VERSION 5.4 ;
NAMESCASESENSITIVE ON ;
BUSBITCHARS "[]" ;
DIVIDERCHAR "/" ;
UNITS
  DATABASE MICRONS 2000 ;
END UNITS
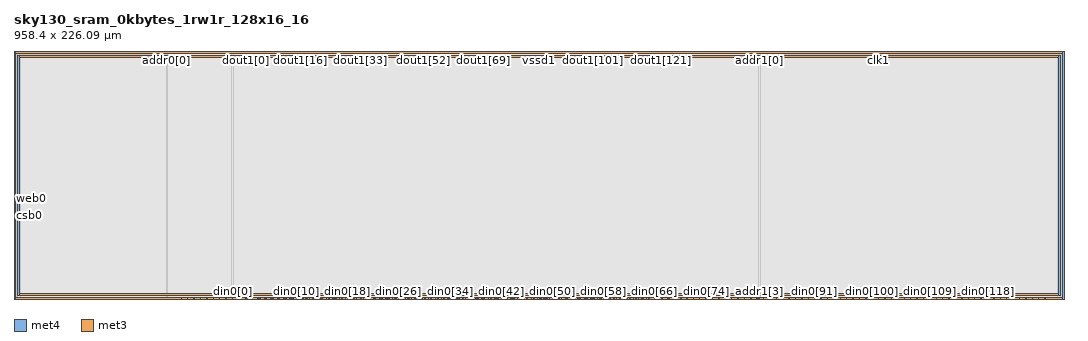
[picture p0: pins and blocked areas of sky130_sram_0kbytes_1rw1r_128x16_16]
MACRO sky130_sram_0kbytes_1rw1r_128x16_16
   CLASS BLOCK ;
   SIZE 958.4 BY 226.09 ;
   SYMMETRY X Y R90 ;
   PIN din0[0]
      DIRECTION INPUT ;
      PORT
         LAYER met4 ;
         RECT  199.3 0.0 199.68 0.38 ;
      END
   END din0[0]
   PIN din0[1]
      DIRECTION INPUT ;
      PORT
         LAYER met4 ;
         RECT  205.14 0.0 205.52 0.38 ;
      END
   END din0[1]
   PIN din0[2]
      DIRECTION INPUT ;
      PORT
         LAYER met4 ;
         RECT  210.98 0.0 211.36 0.38 ;
      END
   END din0[2]
   PIN din0[3]
      DIRECTION INPUT ;
      PORT
         LAYER met4 ;
         RECT  216.82 0.0 217.2 0.38 ;
      END
   END din0[3]
   PIN din0[4]
      DIRECTION INPUT ;
      PORT
         LAYER met4 ;
         RECT  222.66 0.0 223.04 0.38 ;
      END
   END din0[4]
   PIN din0[5]
      DIRECTION INPUT ;
      PORT
         LAYER met4 ;
         RECT  228.5 0.0 228.88 0.38 ;
      END
   END din0[5]
   PIN din0[6]
      DIRECTION INPUT ;
      PORT
         LAYER met4 ;
         RECT  234.34 0.0 234.72 0.38 ;
      END
   END din0[6]
   PIN din0[7]
      DIRECTION INPUT ;
      PORT
         LAYER met4 ;
         RECT  240.18 0.0 240.56 0.38 ;
      END
   END din0[7]
   PIN din0[8]
      DIRECTION INPUT ;
      PORT
         LAYER met4 ;
         RECT  246.02 0.0 246.4 0.38 ;
      END
   END din0[8]
   PIN din0[9]
      DIRECTION INPUT ;
      PORT
         LAYER met4 ;
         RECT  251.86 0.0 252.24 0.38 ;
      END
   END din0[9]
   PIN din0[10]
      DIRECTION INPUT ;
      PORT
         LAYER met4 ;
         RECT  257.7 0.0 258.08 0.38 ;
      END
   END din0[10]
   PIN din0[11]
      DIRECTION INPUT ;
      PORT
         LAYER met4 ;
         RECT  263.54 0.0 263.92 0.38 ;
      END
   END din0[11]
   PIN din0[12]
      DIRECTION INPUT ;
      PORT
         LAYER met4 ;
         RECT  269.38 0.0 269.76 0.38 ;
      END
   END din0[12]
   PIN din0[13]
      DIRECTION INPUT ;
      PORT
         LAYER met4 ;
         RECT  275.22 0.0 275.6 0.38 ;
      END
   END din0[13]
   PIN din0[14]
      DIRECTION INPUT ;
      PORT
         LAYER met4 ;
         RECT  281.06 0.0 281.44 0.38 ;
      END
   END din0[14]
   PIN din0[15]
      DIRECTION INPUT ;
      PORT
         LAYER met4 ;
         RECT  286.9 0.0 287.28 0.38 ;
      END
   END din0[15]
   PIN din0[16]
      DIRECTION INPUT ;
      PORT
         LAYER met4 ;
         RECT  292.74 0.0 293.12 0.38 ;
      END
   END din0[16]
   PIN din0[17]
      DIRECTION INPUT ;
      PORT
         LAYER met4 ;
         RECT  298.58 0.0 298.96 0.38 ;
      END
   END din0[17]
   PIN din0[18]
      DIRECTION INPUT ;
      PORT
         LAYER met4 ;
         RECT  304.42 0.0 304.8 0.38 ;
      END
   END din0[18]
   PIN din0[19]
      DIRECTION INPUT ;
      PORT
         LAYER met4 ;
         RECT  310.26 0.0 310.64 0.38 ;
      END
   END din0[19]
   PIN din0[20]
      DIRECTION INPUT ;
      PORT
         LAYER met4 ;
         RECT  316.1 0.0 316.48 0.38 ;
      END
   END din0[20]
   PIN din0[21]
      DIRECTION INPUT ;
      PORT
         LAYER met4 ;
         RECT  321.94 0.0 322.32 0.38 ;
      END
   END din0[21]
   PIN din0[22]
      DIRECTION INPUT ;
      PORT
         LAYER met4 ;
         RECT  327.78 0.0 328.16 0.38 ;
      END
   END din0[22]
   PIN din0[23]
      DIRECTION INPUT ;
      PORT
         LAYER met4 ;
         RECT  333.62 0.0 334.0 0.38 ;
      END
   END din0[23]
   PIN din0[24]
      DIRECTION INPUT ;
      PORT
         LAYER met4 ;
         RECT  339.46 0.0 339.84 0.38 ;
      END
   END din0[24]
   PIN din0[25]
      DIRECTION INPUT ;
      PORT
         LAYER met4 ;
         RECT  345.3 0.0 345.68 0.38 ;
      END
   END din0[25]
   PIN din0[26]
      DIRECTION INPUT ;
      PORT
         LAYER met4 ;
         RECT  351.14 0.0 351.52 0.38 ;
      END
   END din0[26]
   PIN din0[27]
      DIRECTION INPUT ;
      PORT
         LAYER met4 ;
         RECT  356.98 0.0 357.36 0.38 ;
      END
   END din0[27]
   PIN din0[28]
      DIRECTION INPUT ;
      PORT
         LAYER met4 ;
         RECT  362.82 0.0 363.2 0.38 ;
      END
   END din0[28]
   PIN din0[29]
      DIRECTION INPUT ;
      PORT
         LAYER met4 ;
         RECT  368.66 0.0 369.04 0.38 ;
      END
   END din0[29]
   PIN din0[30]
      DIRECTION INPUT ;
      PORT
         LAYER met4 ;
         RECT  374.5 0.0 374.88 0.38 ;
      END
   END din0[30]
   PIN din0[31]
      DIRECTION INPUT ;
      PORT
         LAYER met4 ;
         RECT  380.34 0.0 380.72 0.38 ;
      END
   END din0[31]
   PIN din0[32]
      DIRECTION INPUT ;
      PORT
         LAYER met4 ;
         RECT  386.18 0.0 386.56 0.38 ;
      END
   END din0[32]
   PIN din0[33]
      DIRECTION INPUT ;
      PORT
         LAYER met4 ;
         RECT  392.02 0.0 392.4 0.38 ;
      END
   END din0[33]
   PIN din0[34]
      DIRECTION INPUT ;
      PORT
         LAYER met4 ;
         RECT  397.86 0.0 398.24 0.38 ;
      END
   END din0[34]
   PIN din0[35]
      DIRECTION INPUT ;
      PORT
         LAYER met4 ;
         RECT  403.7 0.0 404.08 0.38 ;
      END
   END din0[35]
   PIN din0[36]
      DIRECTION INPUT ;
      PORT
         LAYER met4 ;
         RECT  409.54 0.0 409.92 0.38 ;
      END
   END din0[36]
   PIN din0[37]
      DIRECTION INPUT ;
      PORT
         LAYER met4 ;
         RECT  415.38 0.0 415.76 0.38 ;
      END
   END din0[37]
   PIN din0[38]
      DIRECTION INPUT ;
      PORT
         LAYER met4 ;
         RECT  421.22 0.0 421.6 0.38 ;
      END
   END din0[38]
   PIN din0[39]
      DIRECTION INPUT ;
      PORT
         LAYER met4 ;
         RECT  427.06 0.0 427.44 0.38 ;
      END
   END din0[39]
   PIN din0[40]
      DIRECTION INPUT ;
      PORT
         LAYER met4 ;
         RECT  432.9 0.0 433.28 0.38 ;
      END
   END din0[40]
   PIN din0[41]
      DIRECTION INPUT ;
      PORT
         LAYER met4 ;
         RECT  438.74 0.0 439.12 0.38 ;
      END
   END din0[41]
   PIN din0[42]
      DIRECTION INPUT ;
      PORT
         LAYER met4 ;
         RECT  444.58 0.0 444.96 0.38 ;
      END
   END din0[42]
   PIN din0[43]
      DIRECTION INPUT ;
      PORT
         LAYER met4 ;
         RECT  450.42 0.0 450.8 0.38 ;
      END
   END din0[43]
   PIN din0[44]
      DIRECTION INPUT ;
      PORT
         LAYER met4 ;
         RECT  456.26 0.0 456.64 0.38 ;
      END
   END din0[44]
   PIN din0[45]
      DIRECTION INPUT ;
      PORT
         LAYER met4 ;
         RECT  462.1 0.0 462.48 0.38 ;
      END
   END din0[45]
   PIN din0[46]
      DIRECTION INPUT ;
      PORT
         LAYER met4 ;
         RECT  467.94 0.0 468.32 0.38 ;
      END
   END din0[46]
   PIN din0[47]
      DIRECTION INPUT ;
      PORT
         LAYER met4 ;
         RECT  473.78 0.0 474.16 0.38 ;
      END
   END din0[47]
   PIN din0[48]
      DIRECTION INPUT ;
      PORT
         LAYER met4 ;
         RECT  479.62 0.0 480.0 0.38 ;
      END
   END din0[48]
   PIN din0[49]
      DIRECTION INPUT ;
      PORT
         LAYER met4 ;
         RECT  485.46 0.0 485.84 0.38 ;
      END
   END din0[49]
   PIN din0[50]
      DIRECTION INPUT ;
      PORT
         LAYER met4 ;
         RECT  491.3 0.0 491.68 0.38 ;
      END
   END din0[50]
   PIN din0[51]
      DIRECTION INPUT ;
      PORT
         LAYER met4 ;
         RECT  497.14 0.0 497.52 0.38 ;
      END
   END din0[51]
   PIN din0[52]
      DIRECTION INPUT ;
      PORT
         LAYER met4 ;
         RECT  502.98 0.0 503.36 0.38 ;
      END
   END din0[52]
   PIN din0[53]
      DIRECTION INPUT ;
      PORT
         LAYER met4 ;
         RECT  508.82 0.0 509.2 0.38 ;
      END
   END din0[53]
   PIN din0[54]
      DIRECTION INPUT ;
      PORT
         LAYER met4 ;
         RECT  514.66 0.0 515.04 0.38 ;
      END
   END din0[54]
   PIN din0[55]
      DIRECTION INPUT ;
      PORT
         LAYER met4 ;
         RECT  520.5 0.0 520.88 0.38 ;
      END
   END din0[55]
   PIN din0[56]
      DIRECTION INPUT ;
      PORT
         LAYER met4 ;
         RECT  526.34 0.0 526.72 0.38 ;
      END
   END din0[56]
   PIN din0[57]
      DIRECTION INPUT ;
      PORT
         LAYER met4 ;
         RECT  532.18 0.0 532.56 0.38 ;
      END
   END din0[57]
   PIN din0[58]
      DIRECTION INPUT ;
      PORT
         LAYER met4 ;
         RECT  538.02 0.0 538.4 0.38 ;
      END
   END din0[58]
   PIN din0[59]
      DIRECTION INPUT ;
      PORT
         LAYER met4 ;
         RECT  543.86 0.0 544.24 0.38 ;
      END
   END din0[59]
   PIN din0[60]
      DIRECTION INPUT ;
      PORT
         LAYER met4 ;
         RECT  549.7 0.0 550.08 0.38 ;
      END
   END din0[60]
   PIN din0[61]
      DIRECTION INPUT ;
      PORT
         LAYER met4 ;
         RECT  555.54 0.0 555.92 0.38 ;
      END
   END din0[61]
   PIN din0[62]
      DIRECTION INPUT ;
      PORT
         LAYER met4 ;
         RECT  561.38 0.0 561.76 0.38 ;
      END
   END din0[62]
   PIN din0[63]
      DIRECTION INPUT ;
      PORT
         LAYER met4 ;
         RECT  567.22 0.0 567.6 0.38 ;
      END
   END din0[63]
   PIN din0[64]
      DIRECTION INPUT ;
      PORT
         LAYER met4 ;
         RECT  573.06 0.0 573.44 0.38 ;
      END
   END din0[64]
   PIN din0[65]
      DIRECTION INPUT ;
      PORT
         LAYER met4 ;
         RECT  578.9 0.0 579.28 0.38 ;
      END
   END din0[65]
   PIN din0[66]
      DIRECTION INPUT ;
      PORT
         LAYER met4 ;
         RECT  584.74 0.0 585.12 0.38 ;
      END
   END din0[66]
   PIN din0[67]
      DIRECTION INPUT ;
      PORT
         LAYER met4 ;
         RECT  590.58 0.0 590.96 0.38 ;
      END
   END din0[67]
   PIN din0[68]
      DIRECTION INPUT ;
      PORT
         LAYER met4 ;
         RECT  596.42 0.0 596.8 0.38 ;
      END
   END din0[68]
   PIN din0[69]
      DIRECTION INPUT ;
      PORT
         LAYER met4 ;
         RECT  602.26 0.0 602.64 0.38 ;
      END
   END din0[69]
   PIN din0[70]
      DIRECTION INPUT ;
      PORT
         LAYER met4 ;
         RECT  608.1 0.0 608.48 0.38 ;
      END
   END din0[70]
   PIN din0[71]
      DIRECTION INPUT ;
      PORT
         LAYER met4 ;
         RECT  613.94 0.0 614.32 0.38 ;
      END
   END din0[71]
   PIN din0[72]
      DIRECTION INPUT ;
      PORT
         LAYER met4 ;
         RECT  619.78 0.0 620.16 0.38 ;
      END
   END din0[72]
   PIN din0[73]
      DIRECTION INPUT ;
      PORT
         LAYER met4 ;
         RECT  625.62 0.0 626.0 0.38 ;
      END
   END din0[73]
   PIN din0[74]
      DIRECTION INPUT ;
      PORT
         LAYER met4 ;
         RECT  631.46 0.0 631.84 0.38 ;
      END
   END din0[74]
   PIN din0[75]
      DIRECTION INPUT ;
      PORT
         LAYER met4 ;
         RECT  637.3 0.0 637.68 0.38 ;
      END
   END din0[75]
   PIN din0[76]
      DIRECTION INPUT ;
      PORT
         LAYER met4 ;
         RECT  643.14 0.0 643.52 0.38 ;
      END
   END din0[76]
   PIN din0[77]
      DIRECTION INPUT ;
      PORT
         LAYER met4 ;
         RECT  648.98 0.0 649.36 0.38 ;
      END
   END din0[77]
   PIN din0[78]
      DIRECTION INPUT ;
      PORT
         LAYER met4 ;
         RECT  654.82 0.0 655.2 0.38 ;
      END
   END din0[78]
   PIN din0[79]
      DIRECTION INPUT ;
      PORT
         LAYER met4 ;
         RECT  660.66 0.0 661.04 0.38 ;
      END
   END din0[79]
   PIN din0[80]
      DIRECTION INPUT ;
      PORT
         LAYER met4 ;
         RECT  666.5 0.0 666.88 0.38 ;
      END
   END din0[80]
   PIN din0[81]
      DIRECTION INPUT ;
      PORT
         LAYER met4 ;
         RECT  672.34 0.0 672.72 0.38 ;
      END
   END din0[81]
   PIN din0[82]
      DIRECTION INPUT ;
      PORT
         LAYER met4 ;
         RECT  678.18 0.0 678.56 0.38 ;
      END
   END din0[82]
   PIN din0[83]
      DIRECTION INPUT ;
      PORT
         LAYER met4 ;
         RECT  684.02 0.0 684.4 0.38 ;
      END
   END din0[83]
   PIN din0[84]
      DIRECTION INPUT ;
      PORT
         LAYER met4 ;
         RECT  689.86 0.0 690.24 0.38 ;
      END
   END din0[84]
   PIN din0[85]
      DIRECTION INPUT ;
      PORT
         LAYER met4 ;
         RECT  695.7 0.0 696.08 0.38 ;
      END
   END din0[85]
   PIN din0[86]
      DIRECTION INPUT ;
      PORT
         LAYER met4 ;
         RECT  701.54 0.0 701.92 0.38 ;
      END
   END din0[86]
   PIN din0[87]
      DIRECTION INPUT ;
      PORT
         LAYER met4 ;
         RECT  707.38 0.0 707.76 0.38 ;
      END
   END din0[87]
   PIN din0[88]
      DIRECTION INPUT ;
      PORT
         LAYER met4 ;
         RECT  713.22 0.0 713.6 0.38 ;
      END
   END din0[88]
   PIN din0[89]
      DIRECTION INPUT ;
      PORT
         LAYER met4 ;
         RECT  719.06 0.0 719.44 0.38 ;
      END
   END din0[89]
   PIN din0[90]
      DIRECTION INPUT ;
      PORT
         LAYER met4 ;
         RECT  724.9 0.0 725.28 0.38 ;
      END
   END din0[90]
   PIN din0[91]
      DIRECTION INPUT ;
      PORT
         LAYER met4 ;
         RECT  730.74 0.0 731.12 0.38 ;
      END
   END din0[91]
   PIN din0[92]
      DIRECTION INPUT ;
      PORT
         LAYER met4 ;
         RECT  736.58 0.0 736.96 0.38 ;
      END
   END din0[92]
   PIN din0[93]
      DIRECTION INPUT ;
      PORT
         LAYER met4 ;
         RECT  742.42 0.0 742.8 0.38 ;
      END
   END din0[93]
   PIN din0[94]
      DIRECTION INPUT ;
      PORT
         LAYER met4 ;
         RECT  748.26 0.0 748.64 0.38 ;
      END
   END din0[94]
   PIN din0[95]
      DIRECTION INPUT ;
      PORT
         LAYER met4 ;
         RECT  754.1 0.0 754.48 0.38 ;
      END
   END din0[95]
   PIN din0[96]
      DIRECTION INPUT ;
      PORT
         LAYER met4 ;
         RECT  759.94 0.0 760.32 0.38 ;
      END
   END din0[96]
   PIN din0[97]
      DIRECTION INPUT ;
      PORT
         LAYER met4 ;
         RECT  765.78 0.0 766.16 0.38 ;
      END
   END din0[97]
   PIN din0[98]
      DIRECTION INPUT ;
      PORT
         LAYER met4 ;
         RECT  771.62 0.0 772.0 0.38 ;
      END
   END din0[98]
   PIN din0[99]
      DIRECTION INPUT ;
      PORT
         LAYER met4 ;
         RECT  777.46 0.0 777.84 0.38 ;
      END
   END din0[99]
   PIN din0[100]
      DIRECTION INPUT ;
      PORT
         LAYER met4 ;
         RECT  783.3 0.0 783.68 0.38 ;
      END
   END din0[100]
   PIN din0[101]
      DIRECTION INPUT ;
      PORT
         LAYER met4 ;
         RECT  789.14 0.0 789.52 0.38 ;
      END
   END din0[101]
   PIN din0[102]
      DIRECTION INPUT ;
      PORT
         LAYER met4 ;
         RECT  794.98 0.0 795.36 0.38 ;
      END
   END din0[102]
   PIN din0[103]
      DIRECTION INPUT ;
      PORT
         LAYER met4 ;
         RECT  800.82 0.0 801.2 0.38 ;
      END
   END din0[103]
   PIN din0[104]
      DIRECTION INPUT ;
      PORT
         LAYER met4 ;
         RECT  806.66 0.0 807.04 0.38 ;
      END
   END din0[104]
   PIN din0[105]
      DIRECTION INPUT ;
      PORT
         LAYER met4 ;
         RECT  812.5 0.0 812.88 0.38 ;
      END
   END din0[105]
   PIN din0[106]
      DIRECTION INPUT ;
      PORT
         LAYER met4 ;
         RECT  818.34 0.0 818.72 0.38 ;
      END
   END din0[106]
   PIN din0[107]
      DIRECTION INPUT ;
      PORT
         LAYER met4 ;
         RECT  824.18 0.0 824.56 0.38 ;
      END
   END din0[107]
   PIN din0[108]
      DIRECTION INPUT ;
      PORT
         LAYER met4 ;
         RECT  830.02 0.0 830.4 0.38 ;
      END
   END din0[108]
   PIN din0[109]
      DIRECTION INPUT ;
      PORT
         LAYER met4 ;
         RECT  835.86 0.0 836.24 0.38 ;
      END
   END din0[109]
   PIN din0[110]
      DIRECTION INPUT ;
      PORT
         LAYER met4 ;
         RECT  841.7 0.0 842.08 0.38 ;
      END
   END din0[110]
   PIN din0[111]
      DIRECTION INPUT ;
      PORT
         LAYER met4 ;
         RECT  847.54 0.0 847.92 0.38 ;
      END
   END din0[111]
   PIN din0[112]
      DIRECTION INPUT ;
      PORT
         LAYER met4 ;
         RECT  853.38 0.0 853.76 0.38 ;
      END
   END din0[112]
   PIN din0[113]
      DIRECTION INPUT ;
      PORT
         LAYER met4 ;
         RECT  859.22 0.0 859.6 0.38 ;
      END
   END din0[113]
   PIN din0[114]
      DIRECTION INPUT ;
      PORT
         LAYER met4 ;
         RECT  865.06 0.0 865.44 0.38 ;
      END
   END din0[114]
   PIN din0[115]
      DIRECTION INPUT ;
      PORT
         LAYER met4 ;
         RECT  870.9 0.0 871.28 0.38 ;
      END
   END din0[115]
   PIN din0[116]
      DIRECTION INPUT ;
      PORT
         LAYER met4 ;
         RECT  876.74 0.0 877.12 0.38 ;
      END
   END din0[116]
   PIN din0[117]
      DIRECTION INPUT ;
      PORT
         LAYER met4 ;
         RECT  882.58 0.0 882.96 0.38 ;
      END
   END din0[117]
   PIN din0[118]
      DIRECTION INPUT ;
      PORT
         LAYER met4 ;
         RECT  888.42 0.0 888.8 0.38 ;
      END
   END din0[118]
   PIN din0[119]
      DIRECTION INPUT ;
      PORT
         LAYER met4 ;
         RECT  894.26 0.0 894.64 0.38 ;
      END
   END din0[119]
   PIN din0[120]
      DIRECTION INPUT ;
      PORT
         LAYER met4 ;
         RECT  900.1 0.0 900.48 0.38 ;
      END
   END din0[120]
   PIN din0[121]
      DIRECTION INPUT ;
      PORT
         LAYER met4 ;
         RECT  905.94 0.0 906.32 0.38 ;
      END
   END din0[121]
   PIN din0[122]
      DIRECTION INPUT ;
      PORT
         LAYER met4 ;
         RECT  911.78 0.0 912.16 0.38 ;
      END
   END din0[122]
   PIN din0[123]
      DIRECTION INPUT ;
      PORT
         LAYER met4 ;
         RECT  917.62 0.0 918.0 0.38 ;
      END
   END din0[123]
   PIN din0[124]
      DIRECTION INPUT ;
      PORT
         LAYER met4 ;
         RECT  923.46 0.0 923.84 0.38 ;
      END
   END din0[124]
   PIN din0[125]
      DIRECTION INPUT ;
      PORT
         LAYER met4 ;
         RECT  929.3 0.0 929.68 0.38 ;
      END
   END din0[125]
   PIN din0[126]
      DIRECTION INPUT ;
      PORT
         LAYER met4 ;
         RECT  935.14 0.0 935.52 0.38 ;
      END
   END din0[126]
   PIN din0[127]
      DIRECTION INPUT ;
      PORT
         LAYER met4 ;
         RECT  940.98 0.0 941.36 0.38 ;
      END
   END din0[127]
   PIN addr0[0]
      DIRECTION INPUT ;
      PORT
         LAYER met4 ;
         RECT  139.36 225.71 139.74 226.09 ;
      END
   END addr0[0]
   PIN addr0[1]
      DIRECTION INPUT ;
      PORT
         LAYER met4 ;
         RECT  142.335 225.71 142.715 226.09 ;
      END
   END addr0[1]
   PIN addr0[2]
      DIRECTION INPUT ;
      PORT
         LAYER met4 ;
         RECT  141.645 225.71 142.025 226.09 ;
      END
   END addr0[2]
   PIN addr0[3]
      DIRECTION INPUT ;
      PORT
         LAYER met4 ;
         RECT  140.9 225.71 141.28 226.09 ;
      END
   END addr0[3]
   PIN addr1[0]
      DIRECTION INPUT ;
      PORT
         LAYER met4 ;
         RECT  679.98 225.71 680.36 226.09 ;
      END
   END addr1[0]
   PIN addr1[1]
      DIRECTION INPUT ;
      PORT
         LAYER met4 ;
         RECT  679.235 225.71 679.615 226.09 ;
      END
   END addr1[1]
   PIN addr1[2]
      DIRECTION INPUT ;
      PORT
         LAYER met4 ;
         RECT  678.545 225.71 678.925 226.09 ;
      END
   END addr1[2]
   PIN addr1[3]
      DIRECTION INPUT ;
      PORT
         LAYER met4 ;
         RECT  679.98 0.0 680.36 0.38 ;
      END
   END addr1[3]
   PIN csb0
      DIRECTION INPUT ;
      PORT
         LAYER met3 ;
         RECT  0.0 75.985 0.38 76.365 ;
      END
   END csb0
   PIN csb1
      DIRECTION INPUT ;
      PORT
         LAYER met4 ;
         RECT  805.47 225.71 805.85 226.09 ;
      END
   END csb1
   PIN web0
      DIRECTION INPUT ;
      PORT
         LAYER met3 ;
         RECT  0.0 84.385 0.38 84.765 ;
      END
   END web0
   PIN clk0
      DIRECTION INPUT ;
      PORT
         LAYER met3 ;
         RECT  0.0 77.475 0.38 77.855 ;
      END
   END clk0
   PIN clk1
      DIRECTION INPUT ;
      PORT
         LAYER met4 ;
         RECT  788.7 225.71 789.08 226.09 ;
      END
   END clk1
   PIN wmask0[0]
      DIRECTION INPUT ;
      PORT
         LAYER met4 ;
         RECT  152.58 0.0 152.96 0.38 ;
      END
   END wmask0[0]
   PIN wmask0[1]
      DIRECTION INPUT ;
      PORT
         LAYER met4 ;
         RECT  158.42 0.0 158.8 0.38 ;
      END
   END wmask0[1]
   PIN wmask0[2]
      DIRECTION INPUT ;
      PORT
         LAYER met4 ;
         RECT  164.26 0.0 164.64 0.38 ;
      END
   END wmask0[2]
   PIN wmask0[3]
      DIRECTION INPUT ;
      PORT
         LAYER met4 ;
         RECT  170.1 0.0 170.48 0.38 ;
      END
   END wmask0[3]
   PIN wmask0[4]
      DIRECTION INPUT ;
      PORT
         LAYER met4 ;
         RECT  175.94 0.0 176.32 0.38 ;
      END
   END wmask0[4]
   PIN wmask0[5]
      DIRECTION INPUT ;
      PORT
         LAYER met4 ;
         RECT  181.78 0.0 182.16 0.38 ;
      END
   END wmask0[5]
   PIN wmask0[6]
      DIRECTION INPUT ;
      PORT
         LAYER met4 ;
         RECT  187.62 0.0 188.0 0.38 ;
      END
   END wmask0[6]
   PIN wmask0[7]
      DIRECTION INPUT ;
      PORT
         LAYER met4 ;
         RECT  193.46 0.0 193.84 0.38 ;
      END
   END wmask0[7]
   PIN dout0[0]
      DIRECTION OUTPUT ;
      PORT
         LAYER met4 ;
         RECT  212.505 0.0 212.885 0.38 ;
      END
   END dout0[0]
   PIN dout0[1]
      DIRECTION OUTPUT ;
      PORT
         LAYER met4 ;
         RECT  214.215 0.0 214.595 0.38 ;
      END
   END dout0[1]
   PIN dout0[2]
      DIRECTION OUTPUT ;
      PORT
         LAYER met4 ;
         RECT  217.51 0.0 217.89 0.38 ;
      END
   END dout0[2]
   PIN dout0[3]
      DIRECTION OUTPUT ;
      PORT
         LAYER met4 ;
         RECT  223.35 0.0 223.73 0.38 ;
      END
   END dout0[3]
   PIN dout0[4]
      DIRECTION OUTPUT ;
      PORT
         LAYER met4 ;
         RECT  224.985 0.0 225.365 0.38 ;
      END
   END dout0[4]
   PIN dout0[5]
      DIRECTION OUTPUT ;
      PORT
         LAYER met4 ;
         RECT  229.19 0.0 229.57 0.38 ;
      END
   END dout0[5]
   PIN dout0[6]
      DIRECTION OUTPUT ;
      PORT
         LAYER met4 ;
         RECT  229.905 0.0 230.285 0.38 ;
      END
   END dout0[6]
   PIN dout0[7]
      DIRECTION OUTPUT ;
      PORT
         LAYER met4 ;
         RECT  235.03 0.0 235.41 0.38 ;
      END
   END dout0[7]
   PIN dout0[8]
      DIRECTION OUTPUT ;
      PORT
         LAYER met4 ;
         RECT  236.085 0.0 236.465 0.38 ;
      END
   END dout0[8]
   PIN dout0[9]
      DIRECTION OUTPUT ;
      PORT
         LAYER met4 ;
         RECT  241.115 0.0 241.495 0.38 ;
      END
   END dout0[9]
   PIN dout0[10]
      DIRECTION OUTPUT ;
      PORT
         LAYER met4 ;
         RECT  242.325 0.0 242.705 0.38 ;
      END
   END dout0[10]
   PIN dout0[11]
      DIRECTION OUTPUT ;
      PORT
         LAYER met4 ;
         RECT  247.355 0.0 247.735 0.38 ;
      END
   END dout0[11]
   PIN dout0[12]
      DIRECTION OUTPUT ;
      PORT
         LAYER met4 ;
         RECT  248.565 0.0 248.945 0.38 ;
      END
   END dout0[12]
   PIN dout0[13]
      DIRECTION OUTPUT ;
      PORT
         LAYER met4 ;
         RECT  253.595 0.0 253.975 0.38 ;
      END
   END dout0[13]
   PIN dout0[14]
      DIRECTION OUTPUT ;
      PORT
         LAYER met4 ;
         RECT  254.805 0.0 255.185 0.38 ;
      END
   END dout0[14]
   PIN dout0[15]
      DIRECTION OUTPUT ;
      PORT
         LAYER met4 ;
         RECT  259.78 0.0 260.16 0.38 ;
      END
   END dout0[15]
   PIN dout0[16]
      DIRECTION OUTPUT ;
      PORT
         LAYER met4 ;
         RECT  261.3 0.0 261.68 0.38 ;
      END
   END dout0[16]
   PIN dout0[17]
      DIRECTION OUTPUT ;
      PORT
         LAYER met4 ;
         RECT  266.075 0.0 266.455 0.38 ;
      END
   END dout0[17]
   PIN dout0[18]
      DIRECTION OUTPUT ;
      PORT
         LAYER met4 ;
         RECT  267.285 0.0 267.665 0.38 ;
      END
   END dout0[18]
   PIN dout0[19]
      DIRECTION OUTPUT ;
      PORT
         LAYER met4 ;
         RECT  272.315 0.0 272.695 0.38 ;
      END
   END dout0[19]
   PIN dout0[20]
      DIRECTION OUTPUT ;
      PORT
         LAYER met4 ;
         RECT  273.415 0.0 273.795 0.38 ;
      END
   END dout0[20]
   PIN dout0[21]
      DIRECTION OUTPUT ;
      PORT
         LAYER met4 ;
         RECT  278.555 0.0 278.935 0.38 ;
      END
   END dout0[21]
   PIN dout0[22]
      DIRECTION OUTPUT ;
      PORT
         LAYER met4 ;
         RECT  279.255 0.0 279.635 0.38 ;
      END
   END dout0[22]
   PIN dout0[23]
      DIRECTION OUTPUT ;
      PORT
         LAYER met4 ;
         RECT  284.795 0.0 285.175 0.38 ;
      END
   END dout0[23]
   PIN dout0[24]
      DIRECTION OUTPUT ;
      PORT
         LAYER met4 ;
         RECT  287.59 0.0 287.97 0.38 ;
      END
   END dout0[24]
   PIN dout0[25]
      DIRECTION OUTPUT ;
      PORT
         LAYER met4 ;
         RECT  290.935 0.0 291.315 0.38 ;
      END
   END dout0[25]
   PIN dout0[26]
      DIRECTION OUTPUT ;
      PORT
         LAYER met4 ;
         RECT  293.625 0.0 294.005 0.38 ;
      END
   END dout0[26]
   PIN dout0[27]
      DIRECTION OUTPUT ;
      PORT
         LAYER met4 ;
         RECT  296.775 0.0 297.155 0.38 ;
      END
   END dout0[27]
   PIN dout0[28]
      DIRECTION OUTPUT ;
      PORT
         LAYER met4 ;
         RECT  299.27 0.0 299.65 0.38 ;
      END
   END dout0[28]
   PIN dout0[29]
      DIRECTION OUTPUT ;
      PORT
         LAYER met4 ;
         RECT  302.615 0.0 302.995 0.38 ;
      END
   END dout0[29]
   PIN dout0[30]
      DIRECTION OUTPUT ;
      PORT
         LAYER met4 ;
         RECT  305.11 0.0 305.49 0.38 ;
      END
   END dout0[30]
   PIN dout0[31]
      DIRECTION OUTPUT ;
      PORT
         LAYER met4 ;
         RECT  307.815 0.0 308.195 0.38 ;
      END
   END dout0[31]
   PIN dout0[32]
      DIRECTION OUTPUT ;
      PORT
         LAYER met4 ;
         RECT  312.345 0.0 312.725 0.38 ;
      END
   END dout0[32]
   PIN dout0[33]
      DIRECTION OUTPUT ;
      PORT
         LAYER met4 ;
         RECT  316.79 0.0 317.17 0.38 ;
      END
   END dout0[33]
   PIN dout0[34]
      DIRECTION OUTPUT ;
      PORT
         LAYER met4 ;
         RECT  318.585 0.0 318.965 0.38 ;
      END
   END dout0[34]
   PIN dout0[35]
      DIRECTION OUTPUT ;
      PORT
         LAYER met4 ;
         RECT  322.63 0.0 323.01 0.38 ;
      END
   END dout0[35]
   PIN dout0[36]
      DIRECTION OUTPUT ;
      PORT
         LAYER met4 ;
         RECT  323.445 0.0 323.825 0.38 ;
      END
   END dout0[36]
   PIN dout0[37]
      DIRECTION OUTPUT ;
      PORT
         LAYER met4 ;
         RECT  328.475 0.0 328.855 0.38 ;
      END
   END dout0[37]
   PIN dout0[38]
      DIRECTION OUTPUT ;
      PORT
         LAYER met4 ;
         RECT  329.685 0.0 330.065 0.38 ;
      END
   END dout0[38]
   PIN dout0[39]
      DIRECTION OUTPUT ;
      PORT
         LAYER met4 ;
         RECT  334.715 0.0 335.095 0.38 ;
      END
   END dout0[39]
   PIN dout0[40]
      DIRECTION OUTPUT ;
      PORT
         LAYER met4 ;
         RECT  335.925 0.0 336.305 0.38 ;
      END
   END dout0[40]
   PIN dout0[41]
      DIRECTION OUTPUT ;
      PORT
         LAYER met4 ;
         RECT  340.955 0.0 341.335 0.38 ;
      END
   END dout0[41]
   PIN dout0[42]
      DIRECTION OUTPUT ;
      PORT
         LAYER met4 ;
         RECT  342.165 0.0 342.545 0.38 ;
      END
   END dout0[42]
   PIN dout0[43]
      DIRECTION OUTPUT ;
      PORT
         LAYER met4 ;
         RECT  347.195 0.0 347.575 0.38 ;
      END
   END dout0[43]
   PIN dout0[44]
      DIRECTION OUTPUT ;
      PORT
         LAYER met4 ;
         RECT  348.405 0.0 348.785 0.38 ;
      END
   END dout0[44]
   PIN dout0[45]
      DIRECTION OUTPUT ;
      PORT
         LAYER met4 ;
         RECT  353.435 0.0 353.815 0.38 ;
      END
   END dout0[45]
   PIN dout0[46]
      DIRECTION OUTPUT ;
      PORT
         LAYER met4 ;
         RECT  354.645 0.0 355.025 0.38 ;
      END
   END dout0[46]
   PIN dout0[47]
      DIRECTION OUTPUT ;
      PORT
         LAYER met4 ;
         RECT  359.62 0.0 360.0 0.38 ;
      END
   END dout0[47]
   PIN dout0[48]
      DIRECTION OUTPUT ;
      PORT
         LAYER met4 ;
         RECT  361.0 0.0 361.38 0.38 ;
      END
   END dout0[48]
   PIN dout0[49]
      DIRECTION OUTPUT ;
      PORT
         LAYER met4 ;
         RECT  365.915 0.0 366.295 0.38 ;
      END
   END dout0[49]
   PIN dout0[50]
      DIRECTION OUTPUT ;
      PORT
         LAYER met4 ;
         RECT  366.855 0.0 367.235 0.38 ;
      END
   END dout0[50]
   PIN dout0[51]
      DIRECTION OUTPUT ;
      PORT
         LAYER met4 ;
         RECT  372.155 0.0 372.535 0.38 ;
      END
   END dout0[51]
   PIN dout0[52]
      DIRECTION OUTPUT ;
      PORT
         LAYER met4 ;
         RECT  375.19 0.0 375.57 0.38 ;
      END
   END dout0[52]
   PIN dout0[53]
      DIRECTION OUTPUT ;
      PORT
         LAYER met4 ;
         RECT  378.395 0.0 378.775 0.38 ;
      END
   END dout0[53]
   PIN dout0[54]
      DIRECTION OUTPUT ;
      PORT
         LAYER met4 ;
         RECT  381.03 0.0 381.41 0.38 ;
      END
   END dout0[54]
   PIN dout0[55]
      DIRECTION OUTPUT ;
      PORT
         LAYER met4 ;
         RECT  384.375 0.0 384.755 0.38 ;
      END
   END dout0[55]
   PIN dout0[56]
      DIRECTION OUTPUT ;
      PORT
         LAYER met4 ;
         RECT  387.225 0.0 387.605 0.38 ;
      END
   END dout0[56]
   PIN dout0[57]
      DIRECTION OUTPUT ;
      PORT
         LAYER met4 ;
         RECT  390.215 0.0 390.595 0.38 ;
      END
   END dout0[57]
   PIN dout0[58]
      DIRECTION OUTPUT ;
      PORT
         LAYER met4 ;
         RECT  392.71 0.0 393.09 0.38 ;
      END
   END dout0[58]
   PIN dout0[59]
      DIRECTION OUTPUT ;
      PORT
         LAYER met4 ;
         RECT  396.055 0.0 396.435 0.38 ;
      END
   END dout0[59]
   PIN dout0[60]
      DIRECTION OUTPUT ;
      PORT
         LAYER met4 ;
         RECT  398.55 0.0 398.93 0.38 ;
      END
   END dout0[60]
   PIN dout0[61]
      DIRECTION OUTPUT ;
      PORT
         LAYER met4 ;
         RECT  404.39 0.0 404.77 0.38 ;
      END
   END dout0[61]
   PIN dout0[62]
      DIRECTION OUTPUT ;
      PORT
         LAYER met4 ;
         RECT  405.945 0.0 406.325 0.38 ;
      END
   END dout0[62]
   PIN dout0[63]
      DIRECTION OUTPUT ;
      PORT
         LAYER met4 ;
         RECT  410.23 0.0 410.61 0.38 ;
      END
   END dout0[63]
   PIN dout0[64]
      DIRECTION OUTPUT ;
      PORT
         LAYER met4 ;
         RECT  412.185 0.0 412.565 0.38 ;
      END
   END dout0[64]
   PIN dout0[65]
      DIRECTION OUTPUT ;
      PORT
         LAYER met4 ;
         RECT  416.07 0.0 416.45 0.38 ;
      END
   END dout0[65]
   PIN dout0[66]
      DIRECTION OUTPUT ;
      PORT
         LAYER met4 ;
         RECT  417.045 0.0 417.425 0.38 ;
      END
   END dout0[66]
   PIN dout0[67]
      DIRECTION OUTPUT ;
      PORT
         LAYER met4 ;
         RECT  422.075 0.0 422.455 0.38 ;
      END
   END dout0[67]
   PIN dout0[68]
      DIRECTION OUTPUT ;
      PORT
         LAYER met4 ;
         RECT  423.285 0.0 423.665 0.38 ;
      END
   END dout0[68]
   PIN dout0[69]
      DIRECTION OUTPUT ;
      PORT
         LAYER met4 ;
         RECT  428.315 0.0 428.695 0.38 ;
      END
   END dout0[69]
   PIN dout0[70]
      DIRECTION OUTPUT ;
      PORT
         LAYER met4 ;
         RECT  429.525 0.0 429.905 0.38 ;
      END
   END dout0[70]
   PIN dout0[71]
      DIRECTION OUTPUT ;
      PORT
         LAYER met4 ;
         RECT  434.555 0.0 434.935 0.38 ;
      END
   END dout0[71]
   PIN dout0[72]
      DIRECTION OUTPUT ;
      PORT
         LAYER met4 ;
         RECT  435.765 0.0 436.145 0.38 ;
      END
   END dout0[72]
   PIN dout0[73]
      DIRECTION OUTPUT ;
      PORT
         LAYER met4 ;
         RECT  440.795 0.0 441.175 0.38 ;
      END
   END dout0[73]
   PIN dout0[74]
      DIRECTION OUTPUT ;
      PORT
         LAYER met4 ;
         RECT  442.005 0.0 442.385 0.38 ;
      END
   END dout0[74]
   PIN dout0[75]
      DIRECTION OUTPUT ;
      PORT
         LAYER met4 ;
         RECT  447.035 0.0 447.415 0.38 ;
      END
   END dout0[75]
   PIN dout0[76]
      DIRECTION OUTPUT ;
      PORT
         LAYER met4 ;
         RECT  448.245 0.0 448.625 0.38 ;
      END
   END dout0[76]
   PIN dout0[77]
      DIRECTION OUTPUT ;
      PORT
         LAYER met4 ;
         RECT  453.275 0.0 453.655 0.38 ;
      END
   END dout0[77]
   PIN dout0[78]
      DIRECTION OUTPUT ;
      PORT
         LAYER met4 ;
         RECT  454.455 0.0 454.835 0.38 ;
      END
   END dout0[78]
   PIN dout0[79]
      DIRECTION OUTPUT ;
      PORT
         LAYER met4 ;
         RECT  459.46 0.0 459.84 0.38 ;
      END
   END dout0[79]
   PIN dout0[80]
      DIRECTION OUTPUT ;
      PORT
         LAYER met4 ;
         RECT  462.79 0.0 463.17 0.38 ;
      END
   END dout0[80]
   PIN dout0[81]
      DIRECTION OUTPUT ;
      PORT
         LAYER met4 ;
         RECT  465.755 0.0 466.135 0.38 ;
      END
   END dout0[81]
   PIN dout0[82]
      DIRECTION OUTPUT ;
      PORT
         LAYER met4 ;
         RECT  468.63 0.0 469.01 0.38 ;
      END
   END dout0[82]
   PIN dout0[83]
      DIRECTION OUTPUT ;
      PORT
         LAYER met4 ;
         RECT  471.975 0.0 472.355 0.38 ;
      END
   END dout0[83]
   PIN dout0[84]
      DIRECTION OUTPUT ;
      PORT
         LAYER met4 ;
         RECT  474.585 0.0 474.965 0.38 ;
      END
   END dout0[84]
   PIN dout0[85]
      DIRECTION OUTPUT ;
      PORT
         LAYER met4 ;
         RECT  477.815 0.0 478.195 0.38 ;
      END
   END dout0[85]
   PIN dout0[86]
      DIRECTION OUTPUT ;
      PORT
         LAYER met4 ;
         RECT  480.825 0.0 481.205 0.38 ;
      END
   END dout0[86]
   PIN dout0[87]
      DIRECTION OUTPUT ;
      PORT
         LAYER met4 ;
         RECT  483.655 0.0 484.035 0.38 ;
      END
   END dout0[87]
   PIN dout0[88]
      DIRECTION OUTPUT ;
      PORT
         LAYER met4 ;
         RECT  486.15 0.0 486.53 0.38 ;
      END
   END dout0[88]
   PIN dout0[89]
      DIRECTION OUTPUT ;
      PORT
         LAYER met4 ;
         RECT  488.775 0.0 489.155 0.38 ;
      END
   END dout0[89]
   PIN dout0[90]
      DIRECTION OUTPUT ;
      PORT
         LAYER met4 ;
         RECT  491.99 0.0 492.37 0.38 ;
      END
   END dout0[90]
   PIN dout0[91]
      DIRECTION OUTPUT ;
      PORT
         LAYER met4 ;
         RECT  497.83 0.0 498.21 0.38 ;
      END
   END dout0[91]
   PIN dout0[92]
      DIRECTION OUTPUT ;
      PORT
         LAYER met4 ;
         RECT  499.545 0.0 499.925 0.38 ;
      END
   END dout0[92]
   PIN dout0[93]
      DIRECTION OUTPUT ;
      PORT
         LAYER met4 ;
         RECT  503.67 0.0 504.05 0.38 ;
      END
   END dout0[93]
   PIN dout0[94]
      DIRECTION OUTPUT ;
      PORT
         LAYER met4 ;
         RECT  504.405 0.0 504.785 0.38 ;
      END
   END dout0[94]
   PIN dout0[95]
      DIRECTION OUTPUT ;
      PORT
         LAYER met4 ;
         RECT  509.51 0.0 509.89 0.38 ;
      END
   END dout0[95]
   PIN dout0[96]
      DIRECTION OUTPUT ;
      PORT
         LAYER met4 ;
         RECT  512.025 0.0 512.405 0.38 ;
      END
   END dout0[96]
   PIN dout0[97]
      DIRECTION OUTPUT ;
      PORT
         LAYER met4 ;
         RECT  515.675 0.0 516.055 0.38 ;
      END
   END dout0[97]
   PIN dout0[98]
      DIRECTION OUTPUT ;
      PORT
         LAYER met4 ;
         RECT  516.885 0.0 517.265 0.38 ;
      END
   END dout0[98]
   PIN dout0[99]
      DIRECTION OUTPUT ;
      PORT
         LAYER met4 ;
         RECT  521.915 0.0 522.295 0.38 ;
      END
   END dout0[99]
   PIN dout0[100]
      DIRECTION OUTPUT ;
      PORT
         LAYER met4 ;
         RECT  523.125 0.0 523.505 0.38 ;
      END
   END dout0[100]
   PIN dout0[101]
      DIRECTION OUTPUT ;
      PORT
         LAYER met4 ;
         RECT  528.155 0.0 528.535 0.38 ;
      END
   END dout0[101]
   PIN dout0[102]
      DIRECTION OUTPUT ;
      PORT
         LAYER met4 ;
         RECT  529.365 0.0 529.745 0.38 ;
      END
   END dout0[102]
   PIN dout0[103]
      DIRECTION OUTPUT ;
      PORT
         LAYER met4 ;
         RECT  534.395 0.0 534.775 0.38 ;
      END
   END dout0[103]
   PIN dout0[104]
      DIRECTION OUTPUT ;
      PORT
         LAYER met4 ;
         RECT  535.605 0.0 535.985 0.38 ;
      END
   END dout0[104]
   PIN dout0[105]
      DIRECTION OUTPUT ;
      PORT
         LAYER met4 ;
         RECT  540.635 0.0 541.015 0.38 ;
      END
   END dout0[105]
   PIN dout0[106]
      DIRECTION OUTPUT ;
      PORT
         LAYER met4 ;
         RECT  541.845 0.0 542.225 0.38 ;
      END
   END dout0[106]
   PIN dout0[107]
      DIRECTION OUTPUT ;
      PORT
         LAYER met4 ;
         RECT  546.875 0.0 547.255 0.38 ;
      END
   END dout0[107]
   PIN dout0[108]
      DIRECTION OUTPUT ;
      PORT
         LAYER met4 ;
         RECT  547.895 0.0 548.275 0.38 ;
      END
   END dout0[108]
   PIN dout0[109]
      DIRECTION OUTPUT ;
      PORT
         LAYER met4 ;
         RECT  553.115 0.0 553.495 0.38 ;
      END
   END dout0[109]
   PIN dout0[110]
      DIRECTION OUTPUT ;
      PORT
         LAYER met4 ;
         RECT  556.23 0.0 556.61 0.38 ;
      END
   END dout0[110]
   PIN dout0[111]
      DIRECTION OUTPUT ;
      PORT
         LAYER met4 ;
         RECT  559.3 0.0 559.68 0.38 ;
      END
   END dout0[111]
   PIN dout0[112]
      DIRECTION OUTPUT ;
      PORT
         LAYER met4 ;
         RECT  562.07 0.0 562.45 0.38 ;
      END
   END dout0[112]
   PIN dout0[113]
      DIRECTION OUTPUT ;
      PORT
         LAYER met4 ;
         RECT  565.415 0.0 565.795 0.38 ;
      END
   END dout0[113]
   PIN dout0[114]
      DIRECTION OUTPUT ;
      PORT
         LAYER met4 ;
         RECT  568.185 0.0 568.565 0.38 ;
      END
   END dout0[114]
   PIN dout0[115]
      DIRECTION OUTPUT ;
      PORT
         LAYER met4 ;
         RECT  569.895 0.0 570.275 0.38 ;
      END
   END dout0[115]
   PIN dout0[116]
      DIRECTION OUTPUT ;
      PORT
         LAYER met4 ;
         RECT  573.75 0.0 574.13 0.38 ;
      END
   END dout0[116]
   PIN dout0[117]
      DIRECTION OUTPUT ;
      PORT
         LAYER met4 ;
         RECT  577.095 0.0 577.475 0.38 ;
      END
   END dout0[117]
   PIN dout0[118]
      DIRECTION OUTPUT ;
      PORT
         LAYER met4 ;
         RECT  579.59 0.0 579.97 0.38 ;
      END
   END dout0[118]
   PIN dout0[119]
      DIRECTION OUTPUT ;
      PORT
         LAYER met4 ;
         RECT  585.43 0.0 585.81 0.38 ;
      END
   END dout0[119]
   PIN dout0[120]
      DIRECTION OUTPUT ;
      PORT
         LAYER met4 ;
         RECT  586.905 0.0 587.285 0.38 ;
      END
   END dout0[120]
   PIN dout0[121]
      DIRECTION OUTPUT ;
      PORT
         LAYER met4 ;
         RECT  591.27 0.0 591.65 0.38 ;
      END
   END dout0[121]
   PIN dout0[122]
      DIRECTION OUTPUT ;
      PORT
         LAYER met4 ;
         RECT  591.96 0.0 592.34 0.38 ;
      END
   END dout0[122]
   PIN dout0[123]
      DIRECTION OUTPUT ;
      PORT
         LAYER met4 ;
         RECT  597.11 0.0 597.49 0.38 ;
      END
   END dout0[123]
   PIN dout0[124]
      DIRECTION OUTPUT ;
      PORT
         LAYER met4 ;
         RECT  598.005 0.0 598.385 0.38 ;
      END
   END dout0[124]
   PIN dout0[125]
      DIRECTION OUTPUT ;
      PORT
         LAYER met4 ;
         RECT  603.035 0.0 603.415 0.38 ;
      END
   END dout0[125]
   PIN dout0[126]
      DIRECTION OUTPUT ;
      PORT
         LAYER met4 ;
         RECT  604.245 0.0 604.625 0.38 ;
      END
   END dout0[126]
   PIN dout0[127]
      DIRECTION OUTPUT ;
      PORT
         LAYER met4 ;
         RECT  609.275 0.0 609.655 0.38 ;
      END
   END dout0[127]
   PIN dout1[0]
      DIRECTION OUTPUT ;
      PORT
         LAYER met4 ;
         RECT  211.185 225.71 211.565 226.09 ;
      END
   END dout1[0]
   PIN dout1[1]
      DIRECTION OUTPUT ;
      PORT
         LAYER met4 ;
         RECT  216.155 225.71 216.535 226.09 ;
      END
   END dout1[1]
   PIN dout1[2]
      DIRECTION OUTPUT ;
      PORT
         LAYER met4 ;
         RECT  217.425 225.71 217.805 226.09 ;
      END
   END dout1[2]
   PIN dout1[3]
      DIRECTION OUTPUT ;
      PORT
         LAYER met4 ;
         RECT  222.395 225.71 222.775 226.09 ;
      END
   END dout1[3]
   PIN dout1[4]
      DIRECTION OUTPUT ;
      PORT
         LAYER met4 ;
         RECT  223.665 225.71 224.045 226.09 ;
      END
   END dout1[4]
   PIN dout1[5]
      DIRECTION OUTPUT ;
      PORT
         LAYER met4 ;
         RECT  228.635 225.71 229.015 226.09 ;
      END
   END dout1[5]
   PIN dout1[6]
      DIRECTION OUTPUT ;
      PORT
         LAYER met4 ;
         RECT  229.905 225.71 230.285 226.09 ;
      END
   END dout1[6]
   PIN dout1[7]
      DIRECTION OUTPUT ;
      PORT
         LAYER met4 ;
         RECT  234.875 225.71 235.255 226.09 ;
      END
   END dout1[7]
   PIN dout1[8]
      DIRECTION OUTPUT ;
      PORT
         LAYER met4 ;
         RECT  236.145 225.71 236.525 226.09 ;
      END
   END dout1[8]
   PIN dout1[9]
      DIRECTION OUTPUT ;
      PORT
         LAYER met4 ;
         RECT  241.115 225.71 241.495 226.09 ;
      END
   END dout1[9]
   PIN dout1[10]
      DIRECTION OUTPUT ;
      PORT
         LAYER met4 ;
         RECT  242.385 225.71 242.765 226.09 ;
      END
   END dout1[10]
   PIN dout1[11]
      DIRECTION OUTPUT ;
      PORT
         LAYER met4 ;
         RECT  247.355 225.71 247.735 226.09 ;
      END
   END dout1[11]
   PIN dout1[12]
      DIRECTION OUTPUT ;
      PORT
         LAYER met4 ;
         RECT  248.625 225.71 249.005 226.09 ;
      END
   END dout1[12]
   PIN dout1[13]
      DIRECTION OUTPUT ;
      PORT
         LAYER met4 ;
         RECT  253.595 225.71 253.975 226.09 ;
      END
   END dout1[13]
   PIN dout1[14]
      DIRECTION OUTPUT ;
      PORT
         LAYER met4 ;
         RECT  254.865 225.71 255.245 226.09 ;
      END
   END dout1[14]
   PIN dout1[15]
      DIRECTION OUTPUT ;
      PORT
         LAYER met4 ;
         RECT  259.835 225.71 260.215 226.09 ;
      END
   END dout1[15]
   PIN dout1[16]
      DIRECTION OUTPUT ;
      PORT
         LAYER met4 ;
         RECT  261.105 225.71 261.485 226.09 ;
      END
   END dout1[16]
   PIN dout1[17]
      DIRECTION OUTPUT ;
      PORT
         LAYER met4 ;
         RECT  266.075 225.71 266.455 226.09 ;
      END
   END dout1[17]
   PIN dout1[18]
      DIRECTION OUTPUT ;
      PORT
         LAYER met4 ;
         RECT  267.345 225.71 267.725 226.09 ;
      END
   END dout1[18]
   PIN dout1[19]
      DIRECTION OUTPUT ;
      PORT
         LAYER met4 ;
         RECT  272.315 225.71 272.695 226.09 ;
      END
   END dout1[19]
   PIN dout1[20]
      DIRECTION OUTPUT ;
      PORT
         LAYER met4 ;
         RECT  273.585 225.71 273.965 226.09 ;
      END
   END dout1[20]
   PIN dout1[21]
      DIRECTION OUTPUT ;
      PORT
         LAYER met4 ;
         RECT  278.555 225.71 278.935 226.09 ;
      END
   END dout1[21]
   PIN dout1[22]
      DIRECTION OUTPUT ;
      PORT
         LAYER met4 ;
         RECT  279.825 225.71 280.205 226.09 ;
      END
   END dout1[22]
   PIN dout1[23]
      DIRECTION OUTPUT ;
      PORT
         LAYER met4 ;
         RECT  284.795 225.71 285.175 226.09 ;
      END
   END dout1[23]
   PIN dout1[24]
      DIRECTION OUTPUT ;
      PORT
         LAYER met4 ;
         RECT  286.065 225.71 286.445 226.09 ;
      END
   END dout1[24]
   PIN dout1[25]
      DIRECTION OUTPUT ;
      PORT
         LAYER met4 ;
         RECT  291.035 225.71 291.415 226.09 ;
      END
   END dout1[25]
   PIN dout1[26]
      DIRECTION OUTPUT ;
      PORT
         LAYER met4 ;
         RECT  292.305 225.71 292.685 226.09 ;
      END
   END dout1[26]
   PIN dout1[27]
      DIRECTION OUTPUT ;
      PORT
         LAYER met4 ;
         RECT  297.275 225.71 297.655 226.09 ;
      END
   END dout1[27]
   PIN dout1[28]
      DIRECTION OUTPUT ;
      PORT
         LAYER met4 ;
         RECT  298.545 225.71 298.925 226.09 ;
      END
   END dout1[28]
   PIN dout1[29]
      DIRECTION OUTPUT ;
      PORT
         LAYER met4 ;
         RECT  303.515 225.71 303.895 226.09 ;
      END
   END dout1[29]
   PIN dout1[30]
      DIRECTION OUTPUT ;
      PORT
         LAYER met4 ;
         RECT  304.785 225.71 305.165 226.09 ;
      END
   END dout1[30]
   PIN dout1[31]
      DIRECTION OUTPUT ;
      PORT
         LAYER met4 ;
         RECT  309.755 225.71 310.135 226.09 ;
      END
   END dout1[31]
   PIN dout1[32]
      DIRECTION OUTPUT ;
      PORT
         LAYER met4 ;
         RECT  311.025 225.71 311.405 226.09 ;
      END
   END dout1[32]
   PIN dout1[33]
      DIRECTION OUTPUT ;
      PORT
         LAYER met4 ;
         RECT  315.995 225.71 316.375 226.09 ;
      END
   END dout1[33]
   PIN dout1[34]
      DIRECTION OUTPUT ;
      PORT
         LAYER met4 ;
         RECT  317.265 225.71 317.645 226.09 ;
      END
   END dout1[34]
   PIN dout1[35]
      DIRECTION OUTPUT ;
      PORT
         LAYER met4 ;
         RECT  322.235 225.71 322.615 226.09 ;
      END
   END dout1[35]
   PIN dout1[36]
      DIRECTION OUTPUT ;
      PORT
         LAYER met4 ;
         RECT  323.505 225.71 323.885 226.09 ;
      END
   END dout1[36]
   PIN dout1[37]
      DIRECTION OUTPUT ;
      PORT
         LAYER met4 ;
         RECT  328.475 225.71 328.855 226.09 ;
      END
   END dout1[37]
   PIN dout1[38]
      DIRECTION OUTPUT ;
      PORT
         LAYER met4 ;
         RECT  329.745 225.71 330.125 226.09 ;
      END
   END dout1[38]
   PIN dout1[39]
      DIRECTION OUTPUT ;
      PORT
         LAYER met4 ;
         RECT  334.715 225.71 335.095 226.09 ;
      END
   END dout1[39]
   PIN dout1[40]
      DIRECTION OUTPUT ;
      PORT
         LAYER met4 ;
         RECT  335.985 225.71 336.365 226.09 ;
      END
   END dout1[40]
   PIN dout1[41]
      DIRECTION OUTPUT ;
      PORT
         LAYER met4 ;
         RECT  340.955 225.71 341.335 226.09 ;
      END
   END dout1[41]
   PIN dout1[42]
      DIRECTION OUTPUT ;
      PORT
         LAYER met4 ;
         RECT  342.225 225.71 342.605 226.09 ;
      END
   END dout1[42]
   PIN dout1[43]
      DIRECTION OUTPUT ;
      PORT
         LAYER met4 ;
         RECT  347.195 225.71 347.575 226.09 ;
      END
   END dout1[43]
   PIN dout1[44]
      DIRECTION OUTPUT ;
      PORT
         LAYER met4 ;
         RECT  348.465 225.71 348.845 226.09 ;
      END
   END dout1[44]
   PIN dout1[45]
      DIRECTION OUTPUT ;
      PORT
         LAYER met4 ;
         RECT  353.435 225.71 353.815 226.09 ;
      END
   END dout1[45]
   PIN dout1[46]
      DIRECTION OUTPUT ;
      PORT
         LAYER met4 ;
         RECT  354.705 225.71 355.085 226.09 ;
      END
   END dout1[46]
   PIN dout1[47]
      DIRECTION OUTPUT ;
      PORT
         LAYER met4 ;
         RECT  359.675 225.71 360.055 226.09 ;
      END
   END dout1[47]
   PIN dout1[48]
      DIRECTION OUTPUT ;
      PORT
         LAYER met4 ;
         RECT  360.945 225.71 361.325 226.09 ;
      END
   END dout1[48]
   PIN dout1[49]
      DIRECTION OUTPUT ;
      PORT
         LAYER met4 ;
         RECT  365.915 225.71 366.295 226.09 ;
      END
   END dout1[49]
   PIN dout1[50]
      DIRECTION OUTPUT ;
      PORT
         LAYER met4 ;
         RECT  367.185 225.71 367.565 226.09 ;
      END
   END dout1[50]
   PIN dout1[51]
      DIRECTION OUTPUT ;
      PORT
         LAYER met4 ;
         RECT  372.155 225.71 372.535 226.09 ;
      END
   END dout1[51]
   PIN dout1[52]
      DIRECTION OUTPUT ;
      PORT
         LAYER met4 ;
         RECT  373.425 225.71 373.805 226.09 ;
      END
   END dout1[52]
   PIN dout1[53]
      DIRECTION OUTPUT ;
      PORT
         LAYER met4 ;
         RECT  378.395 225.71 378.775 226.09 ;
      END
   END dout1[53]
   PIN dout1[54]
      DIRECTION OUTPUT ;
      PORT
         LAYER met4 ;
         RECT  379.665 225.71 380.045 226.09 ;
      END
   END dout1[54]
   PIN dout1[55]
      DIRECTION OUTPUT ;
      PORT
         LAYER met4 ;
         RECT  384.635 225.71 385.015 226.09 ;
      END
   END dout1[55]
   PIN dout1[56]
      DIRECTION OUTPUT ;
      PORT
         LAYER met4 ;
         RECT  385.905 225.71 386.285 226.09 ;
      END
   END dout1[56]
   PIN dout1[57]
      DIRECTION OUTPUT ;
      PORT
         LAYER met4 ;
         RECT  390.875 225.71 391.255 226.09 ;
      END
   END dout1[57]
   PIN dout1[58]
      DIRECTION OUTPUT ;
      PORT
         LAYER met4 ;
         RECT  392.145 225.71 392.525 226.09 ;
      END
   END dout1[58]
   PIN dout1[59]
      DIRECTION OUTPUT ;
      PORT
         LAYER met4 ;
         RECT  397.115 225.71 397.495 226.09 ;
      END
   END dout1[59]
   PIN dout1[60]
      DIRECTION OUTPUT ;
      PORT
         LAYER met4 ;
         RECT  398.385 225.71 398.765 226.09 ;
      END
   END dout1[60]
   PIN dout1[61]
      DIRECTION OUTPUT ;
      PORT
         LAYER met4 ;
         RECT  403.355 225.71 403.735 226.09 ;
      END
   END dout1[61]
   PIN dout1[62]
      DIRECTION OUTPUT ;
      PORT
         LAYER met4 ;
         RECT  404.625 225.71 405.005 226.09 ;
      END
   END dout1[62]
   PIN dout1[63]
      DIRECTION OUTPUT ;
      PORT
         LAYER met4 ;
         RECT  409.595 225.71 409.975 226.09 ;
      END
   END dout1[63]
   PIN dout1[64]
      DIRECTION OUTPUT ;
      PORT
         LAYER met4 ;
         RECT  410.865 225.71 411.245 226.09 ;
      END
   END dout1[64]
   PIN dout1[65]
      DIRECTION OUTPUT ;
      PORT
         LAYER met4 ;
         RECT  415.835 225.71 416.215 226.09 ;
      END
   END dout1[65]
   PIN dout1[66]
      DIRECTION OUTPUT ;
      PORT
         LAYER met4 ;
         RECT  417.105 225.71 417.485 226.09 ;
      END
   END dout1[66]
   PIN dout1[67]
      DIRECTION OUTPUT ;
      PORT
         LAYER met4 ;
         RECT  422.075 225.71 422.455 226.09 ;
      END
   END dout1[67]
   PIN dout1[68]
      DIRECTION OUTPUT ;
      PORT
         LAYER met4 ;
         RECT  423.345 225.71 423.725 226.09 ;
      END
   END dout1[68]
   PIN dout1[69]
      DIRECTION OUTPUT ;
      PORT
         LAYER met4 ;
         RECT  428.315 225.71 428.695 226.09 ;
      END
   END dout1[69]
   PIN dout1[70]
      DIRECTION OUTPUT ;
      PORT
         LAYER met4 ;
         RECT  429.585 225.71 429.965 226.09 ;
      END
   END dout1[70]
   PIN dout1[71]
      DIRECTION OUTPUT ;
      PORT
         LAYER met4 ;
         RECT  434.555 225.71 434.935 226.09 ;
      END
   END dout1[71]
   PIN dout1[72]
      DIRECTION OUTPUT ;
      PORT
         LAYER met4 ;
         RECT  435.825 225.71 436.205 226.09 ;
      END
   END dout1[72]
   PIN dout1[73]
      DIRECTION OUTPUT ;
      PORT
         LAYER met4 ;
         RECT  440.795 225.71 441.175 226.09 ;
      END
   END dout1[73]
   PIN dout1[74]
      DIRECTION OUTPUT ;
      PORT
         LAYER met4 ;
         RECT  442.065 225.71 442.445 226.09 ;
      END
   END dout1[74]
   PIN dout1[75]
      DIRECTION OUTPUT ;
      PORT
         LAYER met4 ;
         RECT  447.035 225.71 447.415 226.09 ;
      END
   END dout1[75]
   PIN dout1[76]
      DIRECTION OUTPUT ;
      PORT
         LAYER met4 ;
         RECT  448.305 225.71 448.685 226.09 ;
      END
   END dout1[76]
   PIN dout1[77]
      DIRECTION OUTPUT ;
      PORT
         LAYER met4 ;
         RECT  453.275 225.71 453.655 226.09 ;
      END
   END dout1[77]
   PIN dout1[78]
      DIRECTION OUTPUT ;
      PORT
         LAYER met4 ;
         RECT  454.545 225.71 454.925 226.09 ;
      END
   END dout1[78]
   PIN dout1[79]
      DIRECTION OUTPUT ;
      PORT
         LAYER met4 ;
         RECT  459.515 225.71 459.895 226.09 ;
      END
   END dout1[79]
   PIN dout1[80]
      DIRECTION OUTPUT ;
      PORT
         LAYER met4 ;
         RECT  460.785 225.71 461.165 226.09 ;
      END
   END dout1[80]
   PIN dout1[81]
      DIRECTION OUTPUT ;
      PORT
         LAYER met4 ;
         RECT  465.755 225.71 466.135 226.09 ;
      END
   END dout1[81]
   PIN dout1[82]
      DIRECTION OUTPUT ;
      PORT
         LAYER met4 ;
         RECT  467.025 225.71 467.405 226.09 ;
      END
   END dout1[82]
   PIN dout1[83]
      DIRECTION OUTPUT ;
      PORT
         LAYER met4 ;
         RECT  471.995 225.71 472.375 226.09 ;
      END
   END dout1[83]
   PIN dout1[84]
      DIRECTION OUTPUT ;
      PORT
         LAYER met4 ;
         RECT  473.265 225.71 473.645 226.09 ;
      END
   END dout1[84]
   PIN dout1[85]
      DIRECTION OUTPUT ;
      PORT
         LAYER met4 ;
         RECT  478.235 225.71 478.615 226.09 ;
      END
   END dout1[85]
   PIN dout1[86]
      DIRECTION OUTPUT ;
      PORT
         LAYER met4 ;
         RECT  479.505 225.71 479.885 226.09 ;
      END
   END dout1[86]
   PIN dout1[87]
      DIRECTION OUTPUT ;
      PORT
         LAYER met4 ;
         RECT  484.475 225.71 484.855 226.09 ;
      END
   END dout1[87]
   PIN dout1[88]
      DIRECTION OUTPUT ;
      PORT
         LAYER met4 ;
         RECT  485.745 225.71 486.125 226.09 ;
      END
   END dout1[88]
   PIN dout1[89]
      DIRECTION OUTPUT ;
      PORT
         LAYER met4 ;
         RECT  490.715 225.71 491.095 226.09 ;
      END
   END dout1[89]
   PIN dout1[90]
      DIRECTION OUTPUT ;
      PORT
         LAYER met4 ;
         RECT  491.985 225.71 492.365 226.09 ;
      END
   END dout1[90]
   PIN dout1[91]
      DIRECTION OUTPUT ;
      PORT
         LAYER met4 ;
         RECT  496.955 225.71 497.335 226.09 ;
      END
   END dout1[91]
   PIN dout1[92]
      DIRECTION OUTPUT ;
      PORT
         LAYER met4 ;
         RECT  498.225 225.71 498.605 226.09 ;
      END
   END dout1[92]
   PIN dout1[93]
      DIRECTION OUTPUT ;
      PORT
         LAYER met4 ;
         RECT  503.195 225.71 503.575 226.09 ;
      END
   END dout1[93]
   PIN dout1[94]
      DIRECTION OUTPUT ;
      PORT
         LAYER met4 ;
         RECT  504.465 225.71 504.845 226.09 ;
      END
   END dout1[94]
   PIN dout1[95]
      DIRECTION OUTPUT ;
      PORT
         LAYER met4 ;
         RECT  509.435 225.71 509.815 226.09 ;
      END
   END dout1[95]
   PIN dout1[96]
      DIRECTION OUTPUT ;
      PORT
         LAYER met4 ;
         RECT  510.705 225.71 511.085 226.09 ;
      END
   END dout1[96]
   PIN dout1[97]
      DIRECTION OUTPUT ;
      PORT
         LAYER met4 ;
         RECT  515.675 225.71 516.055 226.09 ;
      END
   END dout1[97]
   PIN dout1[98]
      DIRECTION OUTPUT ;
      PORT
         LAYER met4 ;
         RECT  516.945 225.71 517.325 226.09 ;
      END
   END dout1[98]
   PIN dout1[99]
      DIRECTION OUTPUT ;
      PORT
         LAYER met4 ;
         RECT  521.915 225.71 522.295 226.09 ;
      END
   END dout1[99]
   PIN dout1[100]
      DIRECTION OUTPUT ;
      PORT
         LAYER met4 ;
         RECT  523.185 225.71 523.565 226.09 ;
      END
   END dout1[100]
   PIN dout1[101]
      DIRECTION OUTPUT ;
      PORT
         LAYER met4 ;
         RECT  528.155 225.71 528.535 226.09 ;
      END
   END dout1[101]
   PIN dout1[102]
      DIRECTION OUTPUT ;
      PORT
         LAYER met4 ;
         RECT  529.425 225.71 529.805 226.09 ;
      END
   END dout1[102]
   PIN dout1[103]
      DIRECTION OUTPUT ;
      PORT
         LAYER met4 ;
         RECT  534.395 225.71 534.775 226.09 ;
      END
   END dout1[103]
   PIN dout1[104]
      DIRECTION OUTPUT ;
      PORT
         LAYER met4 ;
         RECT  535.665 225.71 536.045 226.09 ;
      END
   END dout1[104]
   PIN dout1[105]
      DIRECTION OUTPUT ;
      PORT
         LAYER met4 ;
         RECT  540.635 225.71 541.015 226.09 ;
      END
   END dout1[105]
   PIN dout1[106]
      DIRECTION OUTPUT ;
      PORT
         LAYER met4 ;
         RECT  541.905 225.71 542.285 226.09 ;
      END
   END dout1[106]
   PIN dout1[107]
      DIRECTION OUTPUT ;
      PORT
         LAYER met4 ;
         RECT  546.875 225.71 547.255 226.09 ;
      END
   END dout1[107]
   PIN dout1[108]
      DIRECTION OUTPUT ;
      PORT
         LAYER met4 ;
         RECT  548.145 225.71 548.525 226.09 ;
      END
   END dout1[108]
   PIN dout1[109]
      DIRECTION OUTPUT ;
      PORT
         LAYER met4 ;
         RECT  553.115 225.71 553.495 226.09 ;
      END
   END dout1[109]
   PIN dout1[110]
      DIRECTION OUTPUT ;
      PORT
         LAYER met4 ;
         RECT  554.385 225.71 554.765 226.09 ;
      END
   END dout1[110]
   PIN dout1[111]
      DIRECTION OUTPUT ;
      PORT
         LAYER met4 ;
         RECT  559.355 225.71 559.735 226.09 ;
      END
   END dout1[111]
   PIN dout1[112]
      DIRECTION OUTPUT ;
      PORT
         LAYER met4 ;
         RECT  560.625 225.71 561.005 226.09 ;
      END
   END dout1[112]
   PIN dout1[113]
      DIRECTION OUTPUT ;
      PORT
         LAYER met4 ;
         RECT  565.595 225.71 565.975 226.09 ;
      END
   END dout1[113]
   PIN dout1[114]
      DIRECTION OUTPUT ;
      PORT
         LAYER met4 ;
         RECT  566.865 225.71 567.245 226.09 ;
      END
   END dout1[114]
   PIN dout1[115]
      DIRECTION OUTPUT ;
      PORT
         LAYER met4 ;
         RECT  571.835 225.71 572.215 226.09 ;
      END
   END dout1[115]
   PIN dout1[116]
      DIRECTION OUTPUT ;
      PORT
         LAYER met4 ;
         RECT  573.105 225.71 573.485 226.09 ;
      END
   END dout1[116]
   PIN dout1[117]
      DIRECTION OUTPUT ;
      PORT
         LAYER met4 ;
         RECT  578.075 225.71 578.455 226.09 ;
      END
   END dout1[117]
   PIN dout1[118]
      DIRECTION OUTPUT ;
      PORT
         LAYER met4 ;
         RECT  579.345 225.71 579.725 226.09 ;
      END
   END dout1[118]
   PIN dout1[119]
      DIRECTION OUTPUT ;
      PORT
         LAYER met4 ;
         RECT  584.315 225.71 584.695 226.09 ;
      END
   END dout1[119]
   PIN dout1[120]
      DIRECTION OUTPUT ;
      PORT
         LAYER met4 ;
         RECT  585.585 225.71 585.965 226.09 ;
      END
   END dout1[120]
   PIN dout1[121]
      DIRECTION OUTPUT ;
      PORT
         LAYER met4 ;
         RECT  590.555 225.71 590.935 226.09 ;
      END
   END dout1[121]
   PIN dout1[122]
      DIRECTION OUTPUT ;
      PORT
         LAYER met4 ;
         RECT  591.825 225.71 592.205 226.09 ;
      END
   END dout1[122]
   PIN dout1[123]
      DIRECTION OUTPUT ;
      PORT
         LAYER met4 ;
         RECT  596.795 225.71 597.175 226.09 ;
      END
   END dout1[123]
   PIN dout1[124]
      DIRECTION OUTPUT ;
      PORT
         LAYER met4 ;
         RECT  598.065 225.71 598.445 226.09 ;
      END
   END dout1[124]
   PIN dout1[125]
      DIRECTION OUTPUT ;
      PORT
         LAYER met4 ;
         RECT  603.035 225.71 603.415 226.09 ;
      END
   END dout1[125]
   PIN dout1[126]
      DIRECTION OUTPUT ;
      PORT
         LAYER met4 ;
         RECT  604.305 225.71 604.685 226.09 ;
      END
   END dout1[126]
   PIN dout1[127]
      DIRECTION OUTPUT ;
      PORT
         LAYER met4 ;
         RECT  609.275 225.71 609.655 226.09 ;
      END
   END dout1[127]
   PIN vccd1
      DIRECTION INOUT ;
      USE POWER ; 
      SHAPE ABUTMENT ; 
      PORT
         LAYER met4 ;
         RECT  0.0 0.0 1.74 226.09 ;
         LAYER met3 ;
         RECT  0.0 224.35 958.4 226.09 ;
         LAYER met3 ;
         RECT  0.0 0.0 958.4 1.74 ;
         LAYER met4 ;
         RECT  956.66 0.0 958.4 226.09 ;
      END
   END vccd1
   PIN vssd1
      DIRECTION INOUT ;
      USE GROUND ; 
      SHAPE ABUTMENT ; 
      PORT
         LAYER met4 ;
         RECT  953.18 3.48 954.92 222.61 ;
         LAYER met3 ;
         RECT  3.48 220.87 954.92 222.61 ;
         LAYER met3 ;
         RECT  3.48 3.48 954.92 5.22 ;
         LAYER met4 ;
         RECT  3.48 3.48 5.22 222.61 ;
      END
   END vssd1
   OBS
   LAYER  met1 ;
      RECT  0.62 0.62 957.78 225.47 ;
   LAYER  met2 ;
      RECT  0.62 0.62 957.78 225.47 ;
   LAYER  met3 ;
      RECT  0.98 75.385 957.78 76.965 ;
      RECT  0.62 78.455 0.98 83.785 ;
      RECT  0.62 85.365 0.98 223.75 ;
      RECT  0.62 2.34 0.98 75.385 ;
      RECT  0.98 76.965 2.88 220.27 ;
      RECT  0.98 220.27 2.88 223.21 ;
      RECT  0.98 223.21 2.88 223.75 ;
      RECT  2.88 76.965 955.52 220.27 ;
      RECT  2.88 223.21 955.52 223.75 ;
      RECT  955.52 76.965 957.78 220.27 ;
      RECT  955.52 220.27 957.78 223.21 ;
      RECT  955.52 223.21 957.78 223.75 ;
      RECT  0.98 2.34 2.88 2.88 ;
      RECT  0.98 2.88 2.88 5.82 ;
      RECT  0.98 5.82 2.88 75.385 ;
      RECT  2.88 2.34 955.52 2.88 ;
      RECT  2.88 5.82 955.52 75.385 ;
      RECT  955.52 2.34 957.78 2.88 ;
      RECT  955.52 2.88 957.78 5.82 ;
      RECT  955.52 5.82 957.78 75.385 ;
   LAYER  met4 ;
      RECT  198.7 0.98 200.28 225.47 ;
      RECT  200.28 0.62 204.54 0.98 ;
      RECT  206.12 0.62 210.38 0.98 ;
      RECT  614.92 0.62 619.18 0.98 ;
      RECT  620.76 0.62 625.02 0.98 ;
      RECT  626.6 0.62 630.86 0.98 ;
      RECT  632.44 0.62 636.7 0.98 ;
      RECT  638.28 0.62 642.54 0.98 ;
      RECT  644.12 0.62 648.38 0.98 ;
      RECT  649.96 0.62 654.22 0.98 ;
      RECT  655.8 0.62 660.06 0.98 ;
      RECT  661.64 0.62 665.9 0.98 ;
      RECT  667.48 0.62 671.74 0.98 ;
      RECT  673.32 0.62 677.58 0.98 ;
      RECT  685.0 0.62 689.26 0.98 ;
      RECT  690.84 0.62 695.1 0.98 ;
      RECT  696.68 0.62 700.94 0.98 ;
      RECT  702.52 0.62 706.78 0.98 ;
      RECT  708.36 0.62 712.62 0.98 ;
      RECT  714.2 0.62 718.46 0.98 ;
      RECT  720.04 0.62 724.3 0.98 ;
      RECT  725.88 0.62 730.14 0.98 ;
      RECT  731.72 0.62 735.98 0.98 ;
      RECT  737.56 0.62 741.82 0.98 ;
      RECT  743.4 0.62 747.66 0.98 ;
      RECT  749.24 0.62 753.5 0.98 ;
      RECT  755.08 0.62 759.34 0.98 ;
      RECT  760.92 0.62 765.18 0.98 ;
      RECT  766.76 0.62 771.02 0.98 ;
      RECT  772.6 0.62 776.86 0.98 ;
      RECT  778.44 0.62 782.7 0.98 ;
      RECT  784.28 0.62 788.54 0.98 ;
      RECT  790.12 0.62 794.38 0.98 ;
      RECT  795.96 0.62 800.22 0.98 ;
      RECT  801.8 0.62 806.06 0.98 ;
      RECT  807.64 0.62 811.9 0.98 ;
      RECT  813.48 0.62 817.74 0.98 ;
      RECT  819.32 0.62 823.58 0.98 ;
      RECT  825.16 0.62 829.42 0.98 ;
      RECT  831.0 0.62 835.26 0.98 ;
      RECT  836.84 0.62 841.1 0.98 ;
      RECT  842.68 0.62 846.94 0.98 ;
      RECT  848.52 0.62 852.78 0.98 ;
      RECT  854.36 0.62 858.62 0.98 ;
      RECT  860.2 0.62 864.46 0.98 ;
      RECT  866.04 0.62 870.3 0.98 ;
      RECT  871.88 0.62 876.14 0.98 ;
      RECT  877.72 0.62 881.98 0.98 ;
      RECT  883.56 0.62 887.82 0.98 ;
      RECT  889.4 0.62 893.66 0.98 ;
      RECT  895.24 0.62 899.5 0.98 ;
      RECT  901.08 0.62 905.34 0.98 ;
      RECT  906.92 0.62 911.18 0.98 ;
      RECT  912.76 0.62 917.02 0.98 ;
      RECT  918.6 0.62 922.86 0.98 ;
      RECT  924.44 0.62 928.7 0.98 ;
      RECT  930.28 0.62 934.54 0.98 ;
      RECT  936.12 0.62 940.38 0.98 ;
      RECT  138.76 0.98 140.34 225.11 ;
      RECT  140.34 0.98 198.7 225.11 ;
      RECT  143.315 225.11 198.7 225.47 ;
      RECT  200.28 0.98 679.38 225.11 ;
      RECT  679.38 0.98 680.96 225.11 ;
      RECT  679.16 0.62 679.38 0.98 ;
      RECT  680.96 0.62 683.42 0.98 ;
      RECT  680.96 225.11 788.1 225.47 ;
      RECT  789.68 225.11 804.87 225.47 ;
      RECT  153.56 0.62 157.82 0.98 ;
      RECT  159.4 0.62 163.66 0.98 ;
      RECT  165.24 0.62 169.5 0.98 ;
      RECT  171.08 0.62 175.34 0.98 ;
      RECT  176.92 0.62 181.18 0.98 ;
      RECT  182.76 0.62 187.02 0.98 ;
      RECT  188.6 0.62 192.86 0.98 ;
      RECT  194.44 0.62 198.7 0.98 ;
      RECT  213.485 0.62 213.615 0.98 ;
      RECT  215.195 0.62 216.22 0.98 ;
      RECT  218.49 0.62 222.06 0.98 ;
      RECT  224.33 0.62 224.385 0.98 ;
      RECT  225.965 0.62 227.9 0.98 ;
      RECT  230.885 0.62 233.74 0.98 ;
      RECT  237.065 0.62 239.58 0.98 ;
      RECT  243.305 0.62 245.42 0.98 ;
      RECT  249.545 0.62 251.26 0.98 ;
      RECT  252.84 0.62 252.995 0.98 ;
      RECT  255.785 0.62 257.1 0.98 ;
      RECT  258.68 0.62 259.18 0.98 ;
      RECT  262.28 0.62 262.94 0.98 ;
      RECT  264.52 0.62 265.475 0.98 ;
      RECT  268.265 0.62 268.78 0.98 ;
      RECT  270.36 0.62 271.715 0.98 ;
      RECT  274.395 0.62 274.62 0.98 ;
      RECT  276.2 0.62 277.955 0.98 ;
      RECT  280.235 0.62 280.46 0.98 ;
      RECT  282.04 0.62 284.195 0.98 ;
      RECT  285.775 0.62 286.3 0.98 ;
      RECT  288.57 0.62 290.335 0.98 ;
      RECT  291.915 0.62 292.14 0.98 ;
      RECT  294.605 0.62 296.175 0.98 ;
      RECT  297.755 0.62 297.98 0.98 ;
      RECT  300.25 0.62 302.015 0.98 ;
      RECT  303.595 0.62 303.82 0.98 ;
      RECT  306.09 0.62 307.215 0.98 ;
      RECT  308.795 0.62 309.66 0.98 ;
      RECT  311.24 0.62 311.745 0.98 ;
      RECT  313.325 0.62 315.5 0.98 ;
      RECT  317.77 0.62 317.985 0.98 ;
      RECT  319.565 0.62 321.34 0.98 ;
      RECT  324.425 0.62 327.18 0.98 ;
      RECT  330.665 0.62 333.02 0.98 ;
      RECT  336.905 0.62 338.86 0.98 ;
      RECT  343.145 0.62 344.7 0.98 ;
      RECT  346.28 0.62 346.595 0.98 ;
      RECT  349.385 0.62 350.54 0.98 ;
      RECT  352.12 0.62 352.835 0.98 ;
      RECT  355.625 0.62 356.38 0.98 ;
      RECT  357.96 0.62 359.02 0.98 ;
      RECT  361.98 0.62 362.22 0.98 ;
      RECT  363.8 0.62 365.315 0.98 ;
      RECT  367.835 0.62 368.06 0.98 ;
      RECT  369.64 0.62 371.555 0.98 ;
      RECT  373.135 0.62 373.9 0.98 ;
      RECT  376.17 0.62 377.795 0.98 ;
      RECT  379.375 0.62 379.74 0.98 ;
      RECT  382.01 0.62 383.775 0.98 ;
      RECT  385.355 0.62 385.58 0.98 ;
      RECT  388.205 0.62 389.615 0.98 ;
      RECT  391.195 0.62 391.42 0.98 ;
      RECT  393.69 0.62 395.455 0.98 ;
      RECT  397.035 0.62 397.26 0.98 ;
      RECT  399.53 0.62 403.1 0.98 ;
      RECT  406.925 0.62 408.94 0.98 ;
      RECT  411.21 0.62 411.585 0.98 ;
      RECT  413.165 0.62 414.78 0.98 ;
      RECT  418.025 0.62 420.62 0.98 ;
      RECT  424.265 0.62 426.46 0.98 ;
      RECT  430.505 0.62 432.3 0.98 ;
      RECT  433.88 0.62 433.955 0.98 ;
      RECT  436.745 0.62 438.14 0.98 ;
      RECT  439.72 0.62 440.195 0.98 ;
      RECT  442.985 0.62 443.98 0.98 ;
      RECT  445.56 0.62 446.435 0.98 ;
      RECT  449.225 0.62 449.82 0.98 ;
      RECT  451.4 0.62 452.675 0.98 ;
      RECT  455.435 0.62 455.66 0.98 ;
      RECT  457.24 0.62 458.86 0.98 ;
      RECT  460.44 0.62 461.5 0.98 ;
      RECT  463.77 0.62 465.155 0.98 ;
      RECT  466.735 0.62 467.34 0.98 ;
      RECT  469.61 0.62 471.375 0.98 ;
      RECT  472.955 0.62 473.18 0.98 ;
      RECT  475.565 0.62 477.215 0.98 ;
      RECT  478.795 0.62 479.02 0.98 ;
      RECT  481.805 0.62 483.055 0.98 ;
      RECT  484.635 0.62 484.86 0.98 ;
      RECT  487.13 0.62 488.175 0.98 ;
      RECT  489.755 0.62 490.7 0.98 ;
      RECT  492.97 0.62 496.54 0.98 ;
      RECT  498.81 0.62 498.945 0.98 ;
      RECT  500.525 0.62 502.38 0.98 ;
      RECT  505.385 0.62 508.22 0.98 ;
      RECT  510.49 0.62 511.425 0.98 ;
      RECT  513.005 0.62 514.06 0.98 ;
      RECT  517.865 0.62 519.9 0.98 ;
      RECT  524.105 0.62 525.74 0.98 ;
      RECT  527.32 0.62 527.555 0.98 ;
      RECT  530.345 0.62 531.58 0.98 ;
      RECT  533.16 0.62 533.795 0.98 ;
      RECT  536.585 0.62 537.42 0.98 ;
      RECT  539.0 0.62 540.035 0.98 ;
      RECT  542.825 0.62 543.26 0.98 ;
      RECT  544.84 0.62 546.275 0.98 ;
      RECT  548.875 0.62 549.1 0.98 ;
      RECT  550.68 0.62 552.515 0.98 ;
      RECT  554.095 0.62 554.94 0.98 ;
      RECT  557.21 0.62 558.7 0.98 ;
      RECT  560.28 0.62 560.78 0.98 ;
      RECT  563.05 0.62 564.815 0.98 ;
      RECT  566.395 0.62 566.62 0.98 ;
      RECT  569.165 0.62 569.295 0.98 ;
      RECT  570.875 0.62 572.46 0.98 ;
      RECT  574.73 0.62 576.495 0.98 ;
      RECT  578.075 0.62 578.3 0.98 ;
      RECT  580.57 0.62 584.14 0.98 ;
      RECT  587.885 0.62 589.98 0.98 ;
      RECT  592.94 0.62 595.82 0.98 ;
      RECT  598.985 0.62 601.66 0.98 ;
      RECT  605.225 0.62 607.5 0.98 ;
      RECT  610.255 0.62 613.34 0.98 ;
      RECT  200.28 225.11 210.585 225.47 ;
      RECT  212.165 225.11 215.555 225.47 ;
      RECT  218.405 225.11 221.795 225.47 ;
      RECT  224.645 225.11 228.035 225.47 ;
      RECT  230.885 225.11 234.275 225.47 ;
      RECT  237.125 225.11 240.515 225.47 ;
      RECT  243.365 225.11 246.755 225.47 ;
      RECT  249.605 225.11 252.995 225.47 ;
      RECT  255.845 225.11 259.235 225.47 ;
      RECT  262.085 225.11 265.475 225.47 ;
      RECT  268.325 225.11 271.715 225.47 ;
      RECT  274.565 225.11 277.955 225.47 ;
      RECT  280.805 225.11 284.195 225.47 ;
      RECT  287.045 225.11 290.435 225.47 ;
      RECT  293.285 225.11 296.675 225.47 ;
      RECT  299.525 225.11 302.915 225.47 ;
      RECT  305.765 225.11 309.155 225.47 ;
      RECT  312.005 225.11 315.395 225.47 ;
      RECT  318.245 225.11 321.635 225.47 ;
      RECT  324.485 225.11 327.875 225.47 ;
      RECT  330.725 225.11 334.115 225.47 ;
      RECT  336.965 225.11 340.355 225.47 ;
      RECT  343.205 225.11 346.595 225.47 ;
      RECT  349.445 225.11 352.835 225.47 ;
      RECT  355.685 225.11 359.075 225.47 ;
      RECT  361.925 225.11 365.315 225.47 ;
      RECT  368.165 225.11 371.555 225.47 ;
      RECT  374.405 225.11 377.795 225.47 ;
      RECT  380.645 225.11 384.035 225.47 ;
      RECT  386.885 225.11 390.275 225.47 ;
      RECT  393.125 225.11 396.515 225.47 ;
      RECT  399.365 225.11 402.755 225.47 ;
      RECT  405.605 225.11 408.995 225.47 ;
      RECT  411.845 225.11 415.235 225.47 ;
      RECT  418.085 225.11 421.475 225.47 ;
      RECT  424.325 225.11 427.715 225.47 ;
      RECT  430.565 225.11 433.955 225.47 ;
      RECT  436.805 225.11 440.195 225.47 ;
      RECT  443.045 225.11 446.435 225.47 ;
      RECT  449.285 225.11 452.675 225.47 ;
      RECT  455.525 225.11 458.915 225.47 ;
      RECT  461.765 225.11 465.155 225.47 ;
      RECT  468.005 225.11 471.395 225.47 ;
      RECT  474.245 225.11 477.635 225.47 ;
      RECT  480.485 225.11 483.875 225.47 ;
      RECT  486.725 225.11 490.115 225.47 ;
      RECT  492.965 225.11 496.355 225.47 ;
      RECT  499.205 225.11 502.595 225.47 ;
      RECT  505.445 225.11 508.835 225.47 ;
      RECT  511.685 225.11 515.075 225.47 ;
      RECT  517.925 225.11 521.315 225.47 ;
      RECT  524.165 225.11 527.555 225.47 ;
      RECT  530.405 225.11 533.795 225.47 ;
      RECT  536.645 225.11 540.035 225.47 ;
      RECT  542.885 225.11 546.275 225.47 ;
      RECT  549.125 225.11 552.515 225.47 ;
      RECT  555.365 225.11 558.755 225.47 ;
      RECT  561.605 225.11 564.995 225.47 ;
      RECT  567.845 225.11 571.235 225.47 ;
      RECT  574.085 225.11 577.475 225.47 ;
      RECT  580.325 225.11 583.715 225.47 ;
      RECT  586.565 225.11 589.955 225.47 ;
      RECT  592.805 225.11 596.195 225.47 ;
      RECT  599.045 225.11 602.435 225.47 ;
      RECT  605.285 225.11 608.675 225.47 ;
      RECT  610.255 225.11 677.945 225.47 ;
      RECT  2.34 225.11 138.76 225.47 ;
      RECT  2.34 0.62 151.98 0.98 ;
      RECT  941.96 0.62 956.06 0.98 ;
      RECT  806.45 225.11 956.06 225.47 ;
      RECT  680.96 0.98 952.58 2.88 ;
      RECT  680.96 2.88 952.58 223.21 ;
      RECT  680.96 223.21 952.58 225.11 ;
      RECT  952.58 0.98 955.52 2.88 ;
      RECT  952.58 223.21 955.52 225.11 ;
      RECT  955.52 0.98 956.06 2.88 ;
      RECT  955.52 2.88 956.06 223.21 ;
      RECT  955.52 223.21 956.06 225.11 ;
      RECT  2.34 0.98 2.88 2.88 ;
      RECT  2.34 2.88 2.88 223.21 ;
      RECT  2.34 223.21 2.88 225.11 ;
      RECT  2.88 0.98 5.82 2.88 ;
      RECT  2.88 223.21 5.82 225.11 ;
      RECT  5.82 0.98 138.76 2.88 ;
      RECT  5.82 2.88 138.76 223.21 ;
      RECT  5.82 223.21 138.76 225.11 ;
   END
END    sky130_sram_0kbytes_1rw1r_128x16_16
END    LIBRARY
